VERSION 5.8 ;
BUSBITCHARS "[]" ;
DIVIDERCHAR "/" ;
UNITS
    DATABASE MICRONS 1000 ;
END UNITS

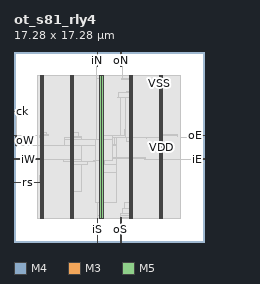
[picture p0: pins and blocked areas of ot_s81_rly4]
MACRO ot_s81_rly4
  FOREIGN ot_s81_rly4 0 0 ;
  CLASS BLOCK ;
  SIZE 17.28 BY 17.28 ;
  PIN ck
    DIRECTION INPUT ;
    USE SIGNAL ;
    PORT
      LAYER M4 ;
        RECT  0 11.856 0.192 11.88 ;
    END
    PORT
      LAYER M4 ;
        RECT  0.156 11.856 0.227 11.88 ;
    END
  END ck
  PIN iE
    DIRECTION INPUT ;
    USE SIGNAL ;
    PORT
      LAYER M4 ;
        RECT  17.088 7.536 17.28 7.56 ;
    END
    PORT
      LAYER M4 ;
        RECT  17.053 7.488 17.1 7.56 ;
    END
  END iE
  PIN iN
    DIRECTION INPUT ;
    USE SIGNAL ;
    PORT
      LAYER M3 ;
        RECT  7.56 17.136 7.578 17.28 ;
    END
    PORT
      LAYER M3 ;
        RECT  7.56 15.997 7.578 17.148 ;
    END
  END iN
  PIN iS
    DIRECTION INPUT ;
    USE SIGNAL ;
    PORT
      LAYER M3 ;
        RECT  7.56 0 7.578 0.144 ;
    END
    PORT
      LAYER M3 ;
        RECT  7.56 0.108 7.578 2.143 ;
    END
  END iS
  PIN iW
    DIRECTION INPUT ;
    USE SIGNAL ;
    PORT
      LAYER M4 ;
        RECT  0 7.536 0.192 7.56 ;
    END
    PORT
      LAYER M4 ;
        RECT  0.156 7.536 2.408 7.56 ;
    END
  END iW
  PIN oE
    DIRECTION OUTPUT ;
    USE SIGNAL ;
    PORT
      LAYER M4 ;
        RECT  17.088 9.696 17.28 9.72 ;
    END
    PORT
      LAYER M4 ;
        RECT  15.973 9.696 17.1 9.72 ;
    END
  END oE
  PIN oN
    DIRECTION OUTPUT ;
    USE SIGNAL ;
    PORT
      LAYER M3 ;
        RECT  9.72 17.136 9.738 17.28 ;
    END
    PORT
      LAYER M3 ;
        RECT  9.72 15.997 9.738 17.148 ;
    END
  END oN
  PIN oS
    DIRECTION OUTPUT ;
    USE SIGNAL ;
    PORT
      LAYER M3 ;
        RECT  9.72 0 9.738 0.144 ;
    END
    PORT
      LAYER M3 ;
        RECT  9.72 0.108 9.738 2.191 ;
    END
  END oS
  PIN oW
    DIRECTION OUTPUT ;
    USE SIGNAL ;
    PORT
      LAYER M4 ;
        RECT  0 9.696 0.192 9.72 ;
    END
    PORT
      LAYER M4 ;
        RECT  0.156 9.696 0.181 9.72 ;
    END
    PORT
      LAYER M4 ;
        RECT  0.181 8.736 0.245 9.72 ;
    END
  END oW
  PIN rs
    DIRECTION INPUT ;
    USE SIGNAL ;
    PORT
      LAYER M4 ;
        RECT  0 5.376 0.192 5.4 ;
    END
    PORT
      LAYER M4 ;
        RECT  0.156 5.376 2.408 5.4 ;
    END
  END rs
  PIN VDD
    DIRECTION INOUT ;
    USE POWER ;
    PORT
      LAYER M5 ;
        RECT  13.392 2.151 13.512 15.129 ;
        RECT  10.692 2.151 10.812 15.129 ;
        RECT  7.992 2.151 8.112 15.129 ;
        RECT  5.292 2.151 5.412 15.129 ;
        RECT  2.592 2.151 2.712 15.129 ;
    END
  END VDD
  PIN VSS
    DIRECTION INOUT ;
    USE GROUND ;
    PORT
      LAYER M5 ;
        RECT  13.2 2.137 13.32 15.143 ;
        RECT  10.5 2.137 10.62 15.143 ;
        RECT  7.8 2.137 7.92 15.143 ;
        RECT  5.1 2.137 5.22 15.143 ;
        RECT  2.4 2.137 2.52 15.143 ;
    END
  END VSS
  # OT_OBS_CLOSED layer=M5 d_um=1.536 added=1
  OBS
    LAYER RVTN ;
     RECT  2.16 2.16 15.12 2.295 ;
     RECT  2.16 2.565 15.12 2.835 ;
     RECT  2.16 3.105 15.12 3.375 ;
     RECT  2.16 3.645 15.12 3.915 ;
     RECT  2.16 4.185 15.12 4.455 ;
     RECT  2.16 4.725 15.12 4.995 ;
     RECT  2.16 5.265 15.12 5.535 ;
     RECT  2.16 5.805 15.12 6.075 ;
     RECT  2.16 6.345 15.12 6.615 ;
     RECT  2.16 6.885 15.12 7.155 ;
     RECT  2.16 7.425 15.12 7.695 ;
     RECT  2.16 7.965 15.12 8.235 ;
     RECT  2.16 8.505 15.12 8.775 ;
     RECT  2.16 9.045 15.12 9.315 ;
     RECT  2.16 9.585 15.12 9.855 ;
     RECT  2.16 10.125 15.12 10.395 ;
     RECT  2.16 10.665 15.12 10.935 ;
     RECT  2.16 11.205 15.12 11.475 ;
     RECT  2.16 11.745 15.12 12.015 ;
     RECT  2.16 12.285 15.12 12.555 ;
     RECT  2.16 12.825 15.12 13.095 ;
     RECT  2.16 13.365 15.12 13.635 ;
     RECT  2.16 13.905 15.12 14.175 ;
     RECT  2.16 14.445 15.12 14.715 ;
     RECT  2.16 14.985 15.12 15.12 ;
    LAYER RVTP ;
     RECT  2.16 2.295 15.12 2.565 ;
     RECT  2.16 2.835 15.12 3.105 ;
     RECT  2.16 3.375 15.12 3.645 ;
     RECT  2.16 3.915 15.12 4.185 ;
     RECT  2.16 4.455 15.12 4.725 ;
     RECT  2.16 4.995 15.12 5.265 ;
     RECT  2.16 5.535 15.12 5.805 ;
     RECT  2.16 6.075 15.12 6.345 ;
     RECT  2.16 6.615 15.12 6.885 ;
     RECT  2.16 7.155 15.12 7.425 ;
     RECT  2.16 7.695 15.12 7.965 ;
     RECT  2.16 8.235 15.12 8.505 ;
     RECT  2.16 8.775 15.12 9.045 ;
     RECT  2.16 9.315 15.12 9.585 ;
     RECT  2.16 9.855 15.12 10.125 ;
     RECT  2.16 10.395 15.12 10.665 ;
     RECT  2.16 10.935 15.12 11.205 ;
     RECT  2.16 11.475 15.12 11.745 ;
     RECT  2.16 12.015 15.12 12.285 ;
     RECT  2.16 12.555 15.12 12.825 ;
     RECT  2.16 13.095 15.12 13.365 ;
     RECT  2.16 13.635 15.12 13.905 ;
     RECT  2.16 14.175 15.12 14.445 ;
     RECT  2.16 14.715 15.12 14.985 ;
    LAYER M1 ;
     RECT  2.16 2.151 15.12 15.129 ;
    LAYER M2 ;
     RECT  0.211 9.666 2.16 9.684 ;
     RECT  7.483 15.966 7.583 15.984 ;
     RECT  9.715 15.966 9.887 15.984 ;
     RECT  2.16 2.151 15.12 15.129 ;
     RECT  15.12 9.486 16.007 9.504 ;
     RECT  17.059 7.506 17.159 7.524 ;
    LAYER M3 ;
     RECT  10.515 2.143 10.605 2.191 ;
     RECT  2.415 2.143 2.505 2.413 ;
     RECT  5.115 2.143 5.205 2.413 ;
     RECT  7.56 2.143 7.905 2.413 ;
     RECT  9.72 2.191 10.605 2.413 ;
     RECT  13.215 2.143 13.305 2.413 ;
     RECT  9.72 2.413 10.797 2.561 ;
     RECT  9.9 2.561 10.797 3.029 ;
     RECT  10.044 3.029 10.797 3.569 ;
     RECT  7.56 2.413 8.097 3.577 ;
     RECT  5.115 2.413 5.397 4.621 ;
     RECT  2.415 2.413 2.697 5.371 ;
     RECT  2.304 5.371 2.697 6.035 ;
     RECT  7.56 3.577 9.306 6.277 ;
     RECT  5.115 4.621 6.102 7.051 ;
     RECT  7.488 6.277 9.306 7.079 ;
     RECT  5.115 7.051 6.714 7.291 ;
     RECT  7.488 7.079 8.262 7.291 ;
     RECT  5.115 7.291 8.262 7.349 ;
     RECT  5.115 7.349 6.102 7.357 ;
     RECT  7.272 7.349 8.154 7.421 ;
     RECT  13.215 2.413 13.497 7.483 ;
     RECT  2.415 6.035 2.697 7.501 ;
     RECT  17.136 7.483 17.154 7.501 ;
     RECT  4.536 7.357 6.102 7.517 ;
     RECT  13.104 7.483 13.497 7.529 ;
     RECT  17.064 7.501 17.154 7.529 ;
     RECT  2.304 7.501 2.697 7.565 ;
     RECT  17.064 7.529 17.082 7.565 ;
     RECT  7.488 7.421 8.154 7.661 ;
     RECT  11.952 7.483 11.97 7.661 ;
     RECT  7.488 7.661 8.097 8.731 ;
     RECT  9.288 7.079 9.306 8.731 ;
     RECT  7.488 8.731 9.306 8.771 ;
     RECT  8.928 8.771 9.306 8.861 ;
     RECT  10.515 3.569 10.797 9.121 ;
     RECT  5.115 7.517 6.102 9.259 ;
     RECT  2.415 7.565 2.697 9.481 ;
     RECT  12.024 9.391 12.042 9.499 ;
     RECT  13.215 7.529 13.497 9.499 ;
     RECT  4.572 9.259 6.102 9.545 ;
     RECT  12.024 9.499 13.497 9.545 ;
     RECT  5.115 9.545 6.102 9.581 ;
     RECT  2.304 9.481 2.697 9.653 ;
     RECT  2.415 9.653 2.697 9.661 ;
     RECT  9.144 8.861 9.306 9.661 ;
     RECT  10.188 9.121 10.797 9.661 ;
     RECT  13.215 9.545 13.497 9.661 ;
     RECT  14.832 9.625 14.85 9.661 ;
     RECT  9.144 9.661 10.797 9.689 ;
     RECT  0.216 9.661 0.234 9.725 ;
     RECT  15.984 9.481 16.002 9.725 ;
     RECT  2.415 9.661 3.15 9.779 ;
     RECT  13.215 9.661 14.85 9.779 ;
     RECT  13.215 9.779 14.346 9.815 ;
     RECT  5.115 9.581 5.85 9.923 ;
     RECT  2.415 9.779 2.97 9.959 ;
     RECT  9.648 9.689 10.797 13.099 ;
     RECT  9.468 13.099 10.797 13.631 ;
     RECT  10.188 13.631 10.797 13.703 ;
     RECT  9.756 14.755 9.774 14.791 ;
     RECT  10.515 13.703 10.797 14.791 ;
     RECT  2.415 9.959 2.697 14.867 ;
     RECT  5.115 9.923 5.397 14.867 ;
     RECT  7.488 8.771 8.097 14.867 ;
     RECT  9.756 14.791 10.797 14.867 ;
     RECT  13.215 9.815 13.497 14.867 ;
     RECT  9.756 14.867 10.605 14.909 ;
     RECT  2.415 14.867 2.505 15.137 ;
     RECT  5.115 14.867 5.205 15.137 ;
     RECT  7.488 14.867 7.905 15.137 ;
     RECT  9.864 14.909 10.605 15.137 ;
     RECT  13.215 14.867 13.305 15.137 ;
     RECT  7.488 15.137 7.506 15.961 ;
     RECT  9.864 15.137 9.882 15.961 ;
     RECT  7.488 15.961 7.578 15.997 ;
     RECT  9.72 15.961 9.882 15.997 ;
    LAYER M4 ;
     RECT  0.245 8.736 2.408 8.76 ;
     RECT  2.408 2.148 2.512 15.132 ;
     RECT  2.512 2.418 2.704 14.862 ;
     RECT  2.704 8.736 4.561 8.76 ;
     RECT  2.704 7.488 5.108 7.512 ;
     RECT  4.561 8.736 5.108 9.288 ;
     RECT  5.108 2.148 5.212 15.132 ;
     RECT  5.212 2.418 5.404 14.862 ;
     RECT  7.261 7.392 7.34 7.416 ;
     RECT  7.381 3.6 7.808 3.624 ;
     RECT  7.34 7.296 7.808 7.416 ;
     RECT  5.404 8.736 7.808 9.288 ;
     RECT  7.808 2.148 7.912 15.132 ;
     RECT  7.912 2.418 8.104 14.862 ;
     RECT  8.104 3.6 8.597 3.624 ;
     RECT  8.104 8.736 8.633 9.72 ;
     RECT  8.104 7.392 8.963 7.656 ;
     RECT  8.633 8.832 8.963 9.72 ;
     RECT  8.963 9.696 10.076 9.72 ;
     RECT  10.076 9.696 10.117 10.248 ;
     RECT  8.963 7.632 10.508 7.656 ;
     RECT  10.117 9.504 10.508 10.248 ;
     RECT  9.457 13.104 10.508 13.128 ;
     RECT  10.508 2.148 10.612 15.132 ;
     RECT  10.612 2.418 10.804 14.862 ;
     RECT  10.804 7.632 11.886 7.656 ;
     RECT  11.886 7.488 11.981 7.656 ;
     RECT  11.981 7.488 13.208 7.512 ;
     RECT  10.804 9.504 13.208 9.528 ;
     RECT  13.208 2.148 13.312 15.132 ;
     RECT  13.312 2.418 13.504 14.862 ;
     RECT  13.504 7.488 17.053 7.512 ;
     RECT  17.1 7.488 17.165 7.512 ;
    LAYER M5 ;
     RECT  2.4 2.137 2.52 2.151 ;
     RECT  5.1 2.137 5.22 2.151 ;
     RECT  7.8 2.137 7.92 2.151 ;
     RECT  10.5 2.137 10.62 2.151 ;
     RECT  13.2 2.137 13.32 2.151 ;
     RECT  7.8 2.151 8.112 3.589 ;
     RECT  7.392 3.589 8.112 7.381 ;
     RECT  7.392 7.381 8.952 9.299 ;
     RECT  10.5 2.151 10.812 9.493 ;
     RECT  7.8 9.299 8.952 9.731 ;
     RECT  0.192 8.725 0.216 11.891 ;
     RECT  10.128 9.493 10.812 13.139 ;
     RECT  2.4 2.151 2.712 15.129 ;
     RECT  5.1 2.151 5.412 15.129 ;
     RECT  7.8 9.731 8.112 15.129 ;
     RECT  10.5 13.139 10.812 15.129 ;
     RECT  13.2 2.151 13.512 15.129 ;
     RECT  2.4 15.129 2.52 15.143 ;
     RECT  5.1 15.129 5.22 15.143 ;
     RECT  7.8 15.129 7.92 15.143 ;
     RECT  10.5 15.129 10.62 15.143 ;
     RECT  13.2 15.129 13.32 15.143 ;
     RECT  8.952 9.493 10.128 9.731 ;
  END
END ot_s81_rly4
END LIBRARY
